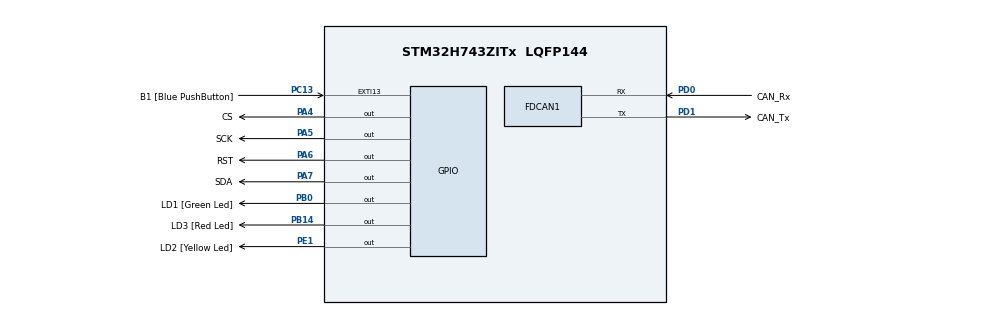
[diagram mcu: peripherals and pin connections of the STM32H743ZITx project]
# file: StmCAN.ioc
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CORTEX_M7.CPU_DCache=Enabled
CORTEX_M7.CPU_ICache=Enabled
FDCAN1.NominalSyncJumpWidth=8
FDCAN1.NominalTimeSeg1=31
FDCAN1.NominalTimeSeg2=8
FDCAN1.RxFifo0ElmtsNbr=1
FDCAN1.StdFiltersNbr=1
FDCAN1.TxFifoQueueElmtsNbr=1
Mcu.Family=STM32H7
Mcu.Name=STM32H743ZITx
Mcu.Package=LQFP144
NVIC.EXTI15_10_IRQn=true\:0\:0\:false\:true\:true\:2\:true\:true
NVIC.FDCAN1_IT0_IRQn=true\:0\:0\:false\:true\:true\:1\:true\:true
NVIC.PriorityGroup=NVIC_PRIORITYGROUP_4
PA4.GPIO_Label=CS
PA4.GPIO_Speed=GPIO_SPEED_FREQ_HIGH
PA4.Signal=GPIO_Output
PA5.GPIO_Label=SCK
PA5.GPIO_Speed=GPIO_SPEED_FREQ_HIGH
PA5.Signal=GPIO_Output
PA6.GPIO_Label=RST
PA6.GPIO_Speed=GPIO_SPEED_FREQ_HIGH
PA6.Signal=GPIO_Output
PA7.GPIO_Label=SDA
PA7.GPIO_Speed=GPIO_SPEED_FREQ_HIGH
PA7.Signal=GPIO_Output
PB0.GPIO_Label=LD1 [Green Led]
PB0.Signal=GPIO_Output
PB14.GPIO_Label=LD3 [Red Led]
PB14.Signal=GPIO_Output
PC13.GPIO_Label=B1 [Blue PushButton]
PC13.Signal=GPXTI13
PD0.GPIO_Label=CAN_Rx
PD0.Mode=FDCANMaster
PD0.Signal=FDCAN1_RX
PD1.GPIO_Label=CAN_Tx
PD1.Mode=FDCANMaster
PD1.Signal=FDCAN1_TX
PE1.GPIO_Label=LD2 [Yellow Led]
PE1.Signal=GPIO_Output
PH0-OSC_IN\ (PH0).Mode=HSE-External-Oscillator
PH0-OSC_IN\ (PH0).Signal=RCC_OSC_IN
PH1-OSC_OUT\ (PH1).Mode=HSE-External-Oscillator
PH1-OSC_OUT\ (PH1).Signal=RCC_OSC_OUT
ProjectManager.HeapSize=0x200
ProjectManager.StackSize=0x400
ProjectManager.TargetToolchain=STM32CubeIDE
RCC.ADCFreq_Value=16125000
RCC.APB1Freq_Value=80000000
RCC.APB2Freq_Value=80000000
RCC.APB3Freq_Value=80000000
RCC.APB4Freq_Value=80000000
RCC.CortexFreq_Value=80000000
RCC.DIVM1=4
RCC.DIVN1=160
RCC.DIVP1=4
RCC.DIVQ1=8
RCC.HCLKFreq_Value=80000000
RCC.HSE_VALUE=8000000
RCC.PLLFRACN=0
RCC.PLLSourceVirtual=RCC_PLLSOURCE_HSE
RCC.SYSCLKFreq_VALUE=80000000
RCC.SYSCLKSource=RCC_SYSCLKSOURCE_PLLCLK
RCC.USBFreq_Value=40000000
board=NUCLEO-H743ZI2

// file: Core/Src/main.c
/* USER CODE BEGIN Header */
/**
  ******************************************************************************
  * @file           : main.c
  * @brief          : Main program body
  ******************************************************************************
  * @attention
  *
  * <h2><center>&copy; Copyright (c) 2019 STMicroelectronics.
  * All rights reserved.</center></h2>
  *
  * This software component is licensed by ST under BSD 3-Clause license,
  * the "License"; You may not use this file except in compliance with the
  * License. You may obtain a copy of the License at:
  *                        opensource.org/licenses/BSD-3-Clause
  *
  ******************************************************************************
  */
/* USER CODE END Header */

#include "main.h"

FDCAN_HandleTypeDef hfdcan1;

void SystemClock_Config(void);
static void MX_GPIO_Init(void);
static void MX_FDCAN1_Init(void);
static void MX_NVIC_Init(void);

int main(void)
{

  /* Enable I-Cache---------------------------------------------------------*/
  SCB_EnableICache();

  /* Enable D-Cache---------------------------------------------------------*/
  SCB_EnableDCache();

  /* MCU Configuration--------------------------------------------------------*/

  /* Reset of all peripherals, Initializes the Flash interface and the Systick. */
  HAL_Init();

  /* Configure the system clock */
  SystemClock_Config();

  /* Initialize all configured peripherals */
  MX_GPIO_Init();
  MX_FDCAN1_Init();

  /* Initialize interrupts */
  MX_NVIC_Init();

  /* Infinite loop */
  while (1)
  {

  }
}

void SystemClock_Config(void)
{
  RCC_OscInitTypeDef RCC_OscInitStruct = {0};
  RCC_ClkInitTypeDef RCC_ClkInitStruct = {0};
  RCC_PeriphCLKInitTypeDef PeriphClkInitStruct = {0};

  /** Supply configuration update enable
  */
  HAL_PWREx_ConfigSupply(PWR_LDO_SUPPLY);
  /** Configure the main internal regulator output voltage
  */
  __HAL_PWR_VOLTAGESCALING_CONFIG(PWR_REGULATOR_VOLTAGE_SCALE3);

  while(!__HAL_PWR_GET_FLAG(PWR_FLAG_VOSRDY)) {}
  /** Initializes the CPU, AHB and APB busses clocks
  */
  RCC_OscInitStruct.OscillatorType = RCC_OSCILLATORTYPE_HSI;
  RCC_OscInitStruct.HSIState = RCC_HSI_DIV1;
  RCC_OscInitStruct.HSICalibrationValue = RCC_HSICALIBRATION_DEFAULT;
  RCC_OscInitStruct.PLL.PLLState = RCC_PLL_ON;
  RCC_OscInitStruct.PLL.PLLSource = RCC_PLLSOURCE_HSI;
  RCC_OscInitStruct.PLL.PLLM = 32;
  RCC_OscInitStruct.PLL.PLLN = 129;
  RCC_OscInitStruct.PLL.PLLP = 2;
  RCC_OscInitStruct.PLL.PLLQ = 2;
  RCC_OscInitStruct.PLL.PLLR = 2;
  RCC_OscInitStruct.PLL.PLLRGE = RCC_PLL1VCIRANGE_1;
  RCC_OscInitStruct.PLL.PLLVCOSEL = RCC_PLL1VCOWIDE;
  RCC_OscInitStruct.PLL.PLLFRACN = 0;
  if (HAL_RCC_OscConfig(&RCC_OscInitStruct) != HAL_OK)
  {
    Error_Handler();
  }
  /** Initializes the CPU, AHB and APB busses clocks
  */
  RCC_ClkInitStruct.ClockType = RCC_CLOCKTYPE_HCLK|RCC_CLOCKTYPE_SYSCLK
                              |RCC_CLOCKTYPE_PCLK1|RCC_CLOCKTYPE_PCLK2
                              |RCC_CLOCKTYPE_D3PCLK1|RCC_CLOCKTYPE_D1PCLK1;
  RCC_ClkInitStruct.SYSCLKSource = RCC_SYSCLKSOURCE_HSI;
  RCC_ClkInitStruct.SYSCLKDivider = RCC_SYSCLK_DIV1;
  RCC_ClkInitStruct.AHBCLKDivider = RCC_HCLK_DIV1;
  RCC_ClkInitStruct.APB3CLKDivider = RCC_APB3_DIV1;
  RCC_ClkInitStruct.APB1CLKDivider = RCC_APB1_DIV1;
  RCC_ClkInitStruct.APB2CLKDivider = RCC_APB2_DIV1;
  RCC_ClkInitStruct.APB4CLKDivider = RCC_APB4_DIV1;

  if (HAL_RCC_ClockConfig(&RCC_ClkInitStruct, FLASH_LATENCY_0) != HAL_OK)
  {
    Error_Handler();
  }
  PeriphClkInitStruct.PeriphClockSelection = RCC_PERIPHCLK_FDCAN;
  PeriphClkInitStruct.FdcanClockSelection = RCC_FDCANCLKSOURCE_PLL;
  if (HAL_RCCEx_PeriphCLKConfig(&PeriphClkInitStruct) != HAL_OK)
  {
    Error_Handler();
  }
}

/**
  * @brief NVIC Configuration.
  * @retval None
  */
static void MX_NVIC_Init(void)
{
  /* FDCAN1_IT0_IRQn interrupt configuration */
  HAL_NVIC_SetPriority(FDCAN1_IT0_IRQn, 0, 0);
  HAL_NVIC_EnableIRQ(FDCAN1_IT0_IRQn);
  /* FDCAN1_IT1_IRQn interrupt configuration */
  HAL_NVIC_SetPriority(FDCAN1_IT1_IRQn, 0, 0);
  HAL_NVIC_EnableIRQ(FDCAN1_IT1_IRQn);
  /* EXTI15_10_IRQn interrupt configuration */
  HAL_NVIC_SetPriority(EXTI15_10_IRQn, 0, 0);
  HAL_NVIC_EnableIRQ(EXTI15_10_IRQn);
}

static void MX_FDCAN1_Init(void)
{

  hfdcan1.Instance = FDCAN1;
  hfdcan1.Init.FrameFormat = FDCAN_FRAME_CLASSIC;
  hfdcan1.Init.Mode = FDCAN_MODE_NORMAL;
  hfdcan1.Init.AutoRetransmission = DISABLE;
  hfdcan1.Init.TransmitPause = DISABLE;
  hfdcan1.Init.ProtocolException = DISABLE;
  hfdcan1.Init.NominalPrescaler = 1;
  hfdcan1.Init.NominalSyncJumpWidth = 1;
  hfdcan1.Init.NominalTimeSeg1 = 2;
  hfdcan1.Init.NominalTimeSeg2 = 2;
  hfdcan1.Init.DataPrescaler = 1;
  hfdcan1.Init.DataSyncJumpWidth = 1;
  hfdcan1.Init.DataTimeSeg1 = 1;
  hfdcan1.Init.DataTimeSeg2 = 1;
  hfdcan1.Init.MessageRAMOffset = 0;
  hfdcan1.Init.StdFiltersNbr = 0;
  hfdcan1.Init.ExtFiltersNbr = 0;
  hfdcan1.Init.RxFifo0ElmtsNbr = 0;
  hfdcan1.Init.RxFifo0ElmtSize = FDCAN_DATA_BYTES_8;
  hfdcan1.Init.RxFifo1ElmtsNbr = 0;
  hfdcan1.Init.RxFifo1ElmtSize = FDCAN_DATA_BYTES_8;
  hfdcan1.Init.RxBuffersNbr = 0;
  hfdcan1.Init.RxBufferSize = FDCAN_DATA_BYTES_8;
  hfdcan1.Init.TxEventsNbr = 0;
  hfdcan1.Init.TxBuffersNbr = 0;
  hfdcan1.Init.TxFifoQueueElmtsNbr = 0;
  hfdcan1.Init.TxFifoQueueMode = FDCAN_TX_FIFO_OPERATION;
  hfdcan1.Init.TxElmtSize = FDCAN_DATA_BYTES_8;
  if (HAL_FDCAN_Init(&hfdcan1) != HAL_OK)
  {
    Error_Handler();
  }

}

static void MX_GPIO_Init(void)
{
  GPIO_InitTypeDef GPIO_InitStruct = {0};

  /* GPIO Ports Clock Enable */
  __HAL_RCC_GPIOC_CLK_ENABLE();
  __HAL_RCC_GPIOB_CLK_ENABLE();
  __HAL_RCC_GPIOD_CLK_ENABLE();
  __HAL_RCC_GPIOE_CLK_ENABLE();

  /*Configure GPIO pin Output Level */
  HAL_GPIO_WritePin(GPIOB, LD1_Pin|LD3_Pin, GPIO_PIN_RESET);

  /*Configure GPIO pin Output Level */
  HAL_GPIO_WritePin(LD2_GPIO_Port, LD2_Pin, GPIO_PIN_RESET);

  /*Configure GPIO pin : B1_Pin */
  GPIO_InitStruct.Pin = B1_Pin;
  GPIO_InitStruct.Mode = GPIO_MODE_IT_RISING;
  GPIO_InitStruct.Pull = GPIO_NOPULL;
  HAL_GPIO_Init(B1_GPIO_Port, &GPIO_InitStruct);

  /*Configure GPIO pins : LD1_Pin LD3_Pin */
  GPIO_InitStruct.Pin = LD1_Pin|LD3_Pin;
  GPIO_InitStruct.Mode = GPIO_MODE_OUTPUT_PP;
  GPIO_InitStruct.Pull = GPIO_NOPULL;
  GPIO_InitStruct.Speed = GPIO_SPEED_FREQ_LOW;
  HAL_GPIO_Init(GPIOB, &GPIO_InitStruct);

  /*Configure GPIO pin : LD2_Pin */
  GPIO_InitStruct.Pin = LD2_Pin;
  GPIO_InitStruct.Mode = GPIO_MODE_OUTPUT_PP;
  GPIO_InitStruct.Pull = GPIO_NOPULL;
  GPIO_InitStruct.Speed = GPIO_SPEED_FREQ_LOW;
  HAL_GPIO_Init(LD2_GPIO_Port, &GPIO_InitStruct);

}

void Error_Handler(void)
{
}

/************************ (C) COPYRIGHT STMicroelectronics *****END OF FILE****/
